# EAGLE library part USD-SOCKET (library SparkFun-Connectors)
microSD Socket Push-push type uSD socket. Schematic element and footprint production proven. Spark Fun Electronics SKU : PRT-00127. tDoc lines correctly indicate media card edge positions when inserting (unlocked, locked, depressed).

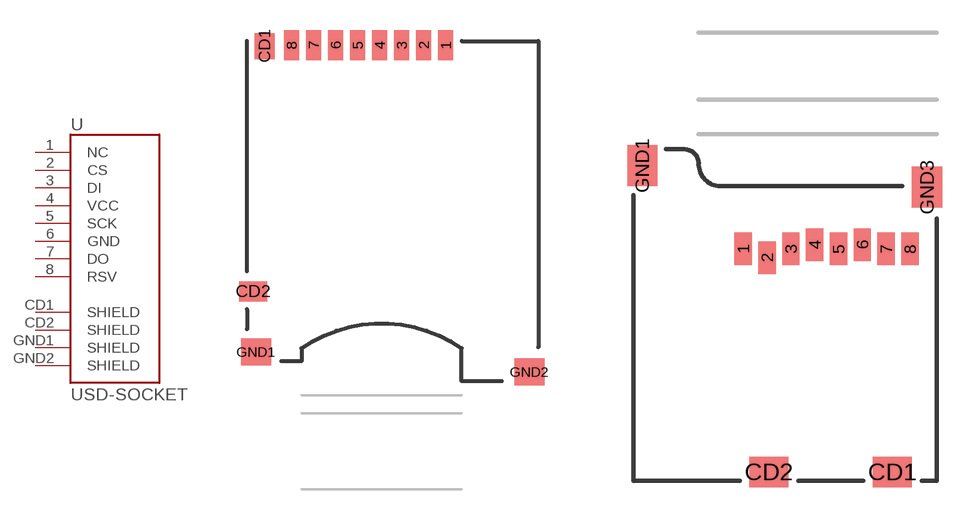
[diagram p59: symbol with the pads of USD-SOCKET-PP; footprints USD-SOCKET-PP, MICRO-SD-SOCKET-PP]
Designator prefix U

## USD-SOCKETUSD  [USD-SOCKET-PP]
1  NC
2  CS
3  DI
4  VCC
5  SCK
6  GND
7  DO
8  RSV
CD1  SHIELD
CD2  SHIELD
GND1  SHIELD
GND2  SHIELD

## USD-SOCKETNEW (PROD_ID: CONN-07820)  [MICRO-SD-SOCKET-PP]
1  NC
2  CS
3  DI
4  VCC
5  SCK
6  GND
7  DO
8  RSV
CD1  SHIELD
CD2  SHIELD
GND1  SHIELD
GND3  SHIELD

## Footprint USD-SOCKET-PP (pad centres in mm)
OLD Production Socket. DO NOT USE for production boards.
smd 0.75 x 1.5: 1 3.2,16.8; 2 2.1,16.8; 3 1,16.8; 4 -0.1,16.8; 5 -1.2,16.8; 6 -2.3,16.8; 7 -3.4,16.8; 8 -4.5,16.8
smd 1 x 1.3: CD1 -5.85,16.75
smd 1.4 x 1: CD2 -6.425,4.5
smd 1.5 x 1.35: GND1 -6.275,1.475; GND2 7.375,0.475

## Footprint MICRO-SD-SOCKET-PP (pad centres in mm)
smd 0.8 x 1.5: 1 -8.94,10.7; 2 -7.84,10.3; 3 -6.74,10.7; 4 -5.64,10.9; 5 -4.54,10.7; 6 -3.44,10.9; 7 -2.34,10.7; 8 -1.24,10.7
smd 1.8 x 1.4: CD1 -2.05,0.4; CD2 -7.75,0.4
smd 1.4 x 1.9: GND1 -13.6,14.55; GND3 -0.45,13.55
